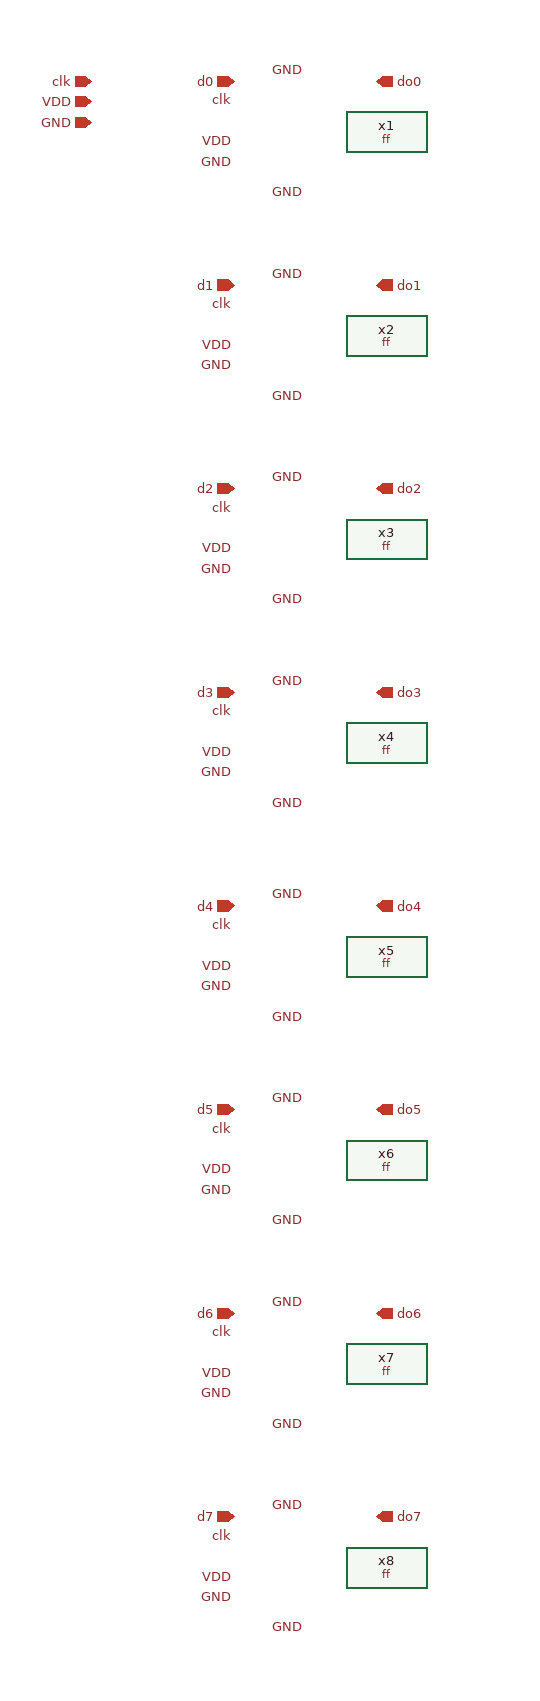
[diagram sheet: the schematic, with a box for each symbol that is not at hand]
v {xschem version=3.4.5 file_version=1.2
}
G {}
K {}
V {}
S {}
E {}
C {ff.sym} 80 -30 0 0 {name=x1}
C {ff.sym} 80 170 0 0 {name=x2}
C {ff.sym} 80 370 0 0 {name=x3}
C {ff.sym} 80 570 0 0 {name=x4}
C {ff.sym} 80 780 0 0 {name=x5}
C {ff.sym} 80 980 0 0 {name=x6}
C {ff.sym} 80 1180 0 0 {name=x7}
C {ff.sym} 80 1380 0 0 {name=x8}
C {devices/ipin.sym} -70 -80 0 0 {name=p4 lab=d0
}
C {devices/ipin.sym} -70 120 0 0 {name=p1 lab=d1
}
C {devices/ipin.sym} -70 320 0 0 {name=p2 lab=d2
}
C {devices/ipin.sym} -70 520 0 0 {name=p3 lab=d3
}
C {devices/ipin.sym} -70 730 0 0 {name=p5 lab=d4
}
C {devices/ipin.sym} -70 930 0 0 {name=p6 lab=d5
}
C {devices/ipin.sym} -70 1130 0 0 {name=p7 lab=d6
}
C {devices/ipin.sym} -70 1330 0 0 {name=p8 lab=d7
}
C {devices/ipin.sym} -210 -80 0 0 {name=p9 lab=clk
}
C {devices/lab_pin.sym} -70 -60 2 1 {name=p12 sig_type=std_logic lab=clk}
C {devices/lab_pin.sym} -70 0 2 1 {name=p10 sig_type=std_logic lab=GND
}
C {devices/lab_pin.sym} -70 -20 2 1 {name=p13 sig_type=std_logic lab=VDD}
C {devices/lab_pin.sym} -70 140 2 1 {name=p11 sig_type=std_logic lab=clk}
C {devices/lab_pin.sym} -70 200 2 1 {name=p14 sig_type=std_logic lab=GND
}
C {devices/lab_pin.sym} -70 180 2 1 {name=p15 sig_type=std_logic lab=VDD}
C {devices/lab_pin.sym} -70 340 2 1 {name=p16 sig_type=std_logic lab=clk}
C {devices/lab_pin.sym} -70 400 2 1 {name=p17 sig_type=std_logic lab=GND
}
C {devices/lab_pin.sym} -70 380 2 1 {name=p18 sig_type=std_logic lab=VDD}
C {devices/lab_pin.sym} -70 540 2 1 {name=p19 sig_type=std_logic lab=clk}
C {devices/lab_pin.sym} -70 600 2 1 {name=p20 sig_type=std_logic lab=GND
}
C {devices/lab_pin.sym} -70 580 2 1 {name=p21 sig_type=std_logic lab=VDD}
C {devices/lab_pin.sym} -70 750 2 1 {name=p22 sig_type=std_logic lab=clk}
C {devices/lab_pin.sym} -70 810 2 1 {name=p23 sig_type=std_logic lab=GND
}
C {devices/lab_pin.sym} -70 790 2 1 {name=p24 sig_type=std_logic lab=VDD}
C {devices/lab_pin.sym} -70 950 2 1 {name=p25 sig_type=std_logic lab=clk}
C {devices/lab_pin.sym} -70 1010 2 1 {name=p26 sig_type=std_logic lab=GND
}
C {devices/lab_pin.sym} -70 990 2 1 {name=p27 sig_type=std_logic lab=VDD}
C {devices/lab_pin.sym} -70 1150 2 1 {name=p28 sig_type=std_logic lab=clk}
C {devices/lab_pin.sym} -70 1210 2 1 {name=p29 sig_type=std_logic lab=GND
}
C {devices/lab_pin.sym} -70 1190 2 1 {name=p30 sig_type=std_logic lab=VDD}
C {devices/lab_pin.sym} -70 1350 2 1 {name=p31 sig_type=std_logic lab=clk}
C {devices/lab_pin.sym} -70 1410 2 1 {name=p32 sig_type=std_logic lab=GND
}
C {devices/lab_pin.sym} -70 1390 2 1 {name=p33 sig_type=std_logic lab=VDD}
C {devices/opin.sym} 70 -80 0 0 {name=p38 lab=do0}
C {devices/opin.sym} 70 120 0 0 {name=p34 lab=do1}
C {devices/opin.sym} 70 320 0 0 {name=p35 lab=do2}
C {devices/opin.sym} 70 520 0 0 {name=p36 lab=do3}
C {devices/opin.sym} 70 730 0 0 {name=p37 lab=do4}
C {devices/opin.sym} 70 930 0 0 {name=p39 lab=do5}
C {devices/opin.sym} 70 1130 0 0 {name=p40 lab=do6}
C {devices/opin.sym} 70 1330 0 0 {name=p41 lab=do7}
C {devices/ipin.sym} -210 -60 0 0 {name=p42 lab=VDD
}
C {devices/ipin.sym} -210 -40 0 0 {name=p43 lab=GND
}
C {devices/lab_pin.sym} 0 30 1 1 {name=p52 sig_type=std_logic lab=GND
}
C {devices/lab_pin.sym} 0 230 1 1 {name=p53 sig_type=std_logic lab=GND
}
C {devices/lab_pin.sym} 0 430 1 1 {name=p54 sig_type=std_logic lab=GND
}
C {devices/lab_pin.sym} 0 630 1 1 {name=p55 sig_type=std_logic lab=GND
}
C {devices/lab_pin.sym} 0 840 1 1 {name=p56 sig_type=std_logic lab=GND
}
C {devices/lab_pin.sym} 0 1040 1 1 {name=p57 sig_type=std_logic lab=GND
}
C {devices/lab_pin.sym} 0 1240 1 1 {name=p58 sig_type=std_logic lab=GND
}
C {devices/lab_pin.sym} 0 1440 1 1 {name=p59 sig_type=std_logic lab=GND
}
C {devices/lab_pin.sym} 0 1320 3 1 {name=p44 sig_type=std_logic lab=GND
}
C {devices/lab_pin.sym} 0 1120 3 1 {name=p45 sig_type=std_logic lab=GND
}
C {devices/lab_pin.sym} 0 920 3 1 {name=p46 sig_type=std_logic lab=GND
}
C {devices/lab_pin.sym} 0 720 3 1 {name=p47 sig_type=std_logic lab=GND
}
C {devices/lab_pin.sym} 0 510 3 1 {name=p48 sig_type=std_logic lab=GND
}
C {devices/lab_pin.sym} 0 310 3 1 {name=p49 sig_type=std_logic lab=GND
}
C {devices/lab_pin.sym} 0 110 3 1 {name=p50 sig_type=std_logic lab=GND
}
C {devices/lab_pin.sym} 0 -90 3 1 {name=p51 sig_type=std_logic lab=GND
}
